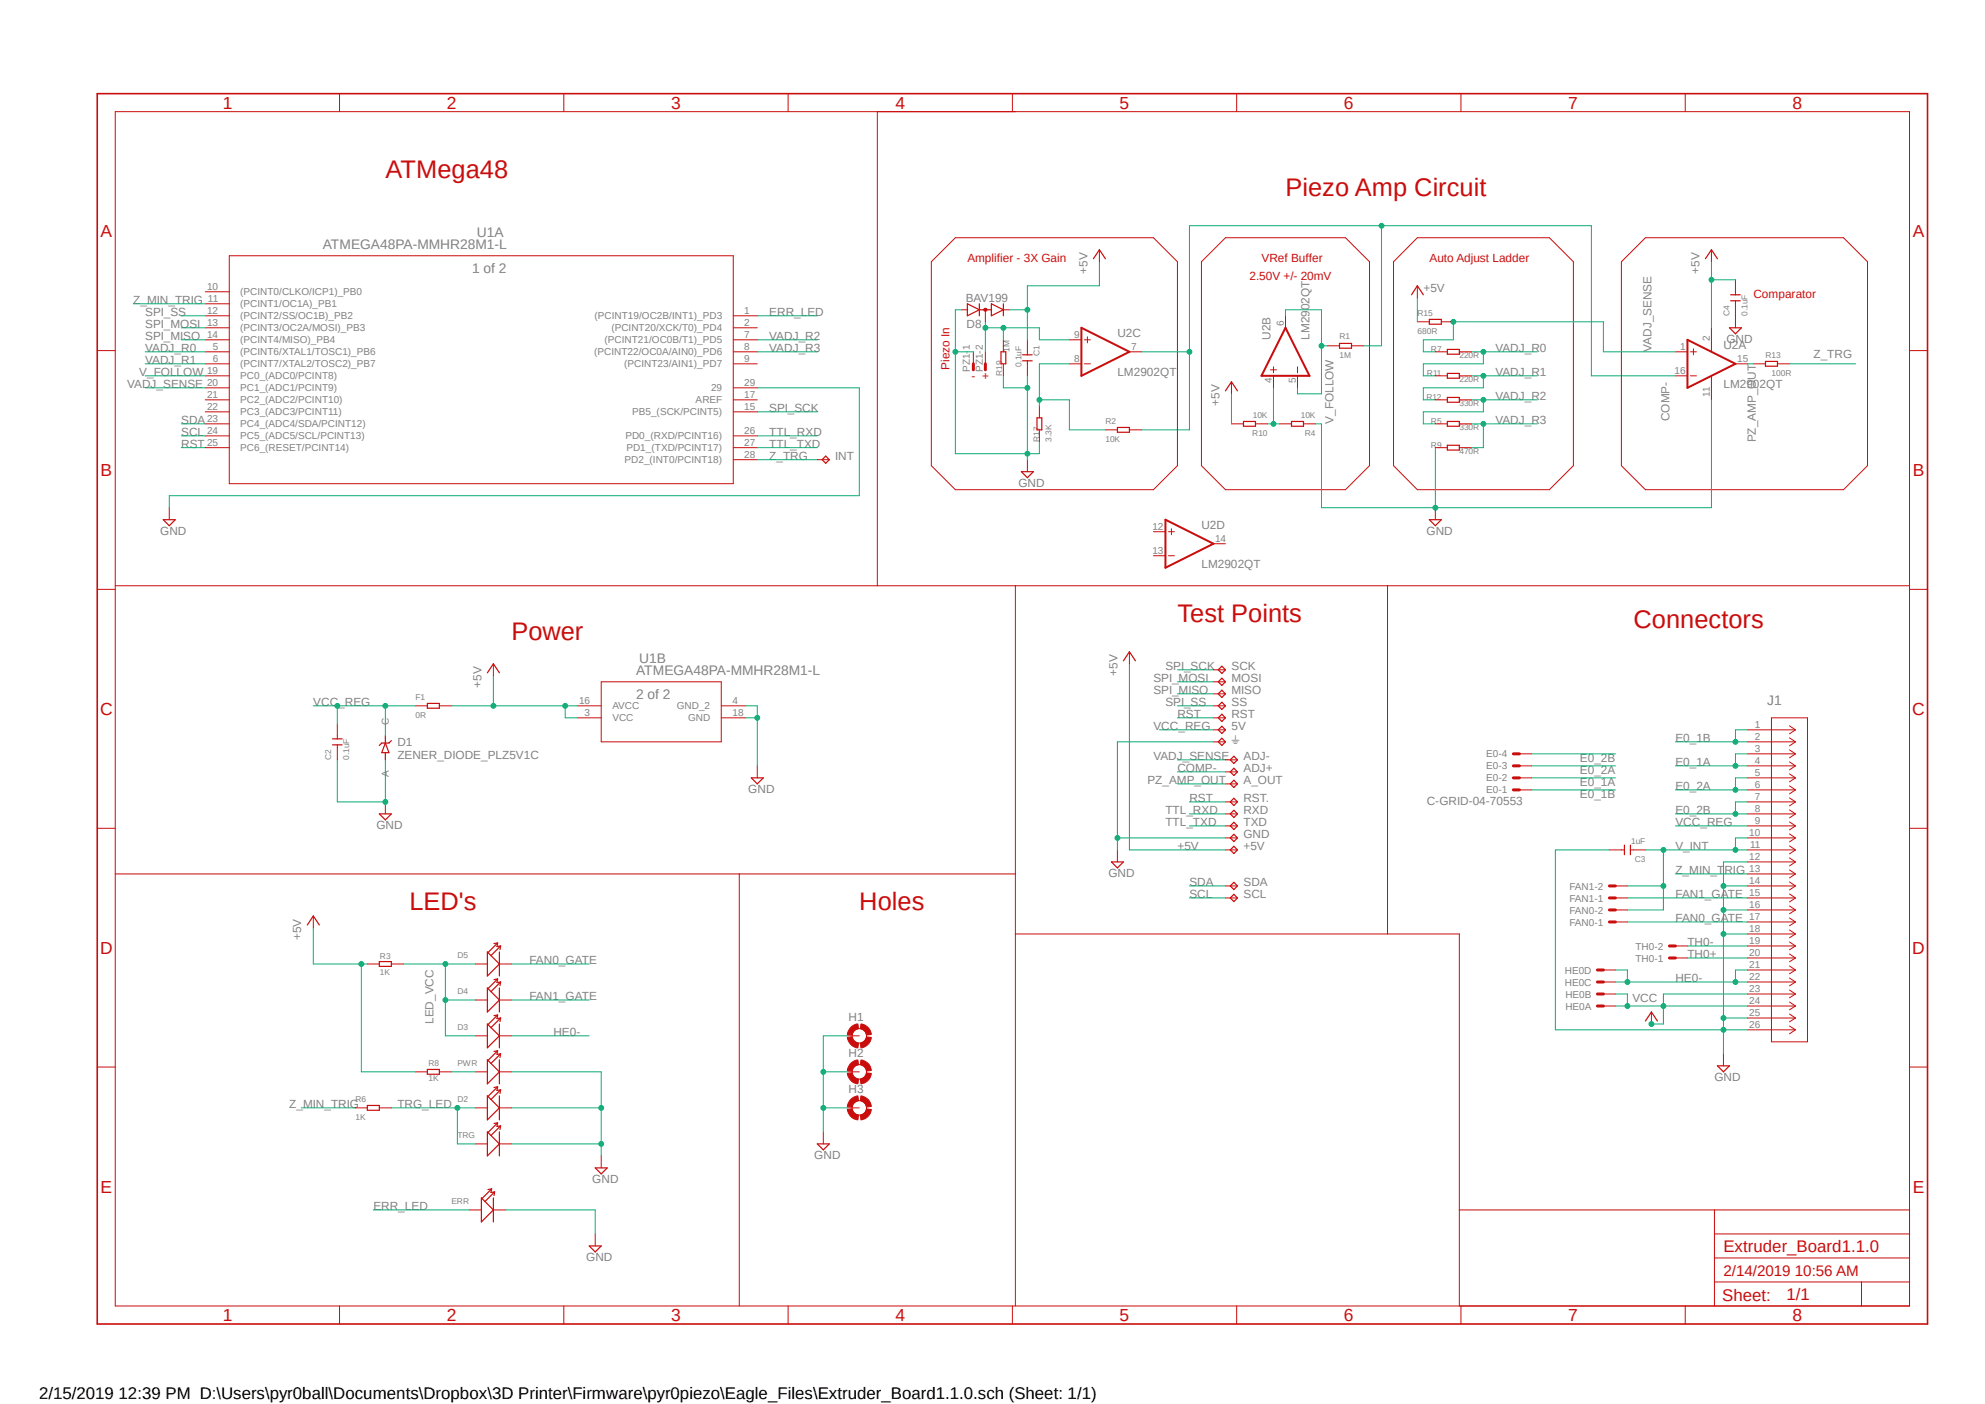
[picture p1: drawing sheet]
<svg xmlns="http://www.w3.org/2000/svg" width="420mm" height="297mm" viewBox="0 0 420 297" stroke-linecap="round" stroke-linejoin="round" font-family="sans-serif">
<defs><g id="words">
<g font-size="5.4" fill="#c90d0c">
<text x="81.5" y="37.6">ATMega48</text>
<text x="272" y="41.4">Piezo Amp Circuit</text>
<text x="249.1" y="131.5">Test Points</text>
<text x="108.2" y="135.3">Power</text>
<text x="345.6" y="132.8">Connectors</text>
<text x="86.6" y="192.5">LED's</text>
<text x="181.8" y="192.5">Holes</text>
</g>
<g font-size="3.7" fill="#c90d0c">
<text x="47.1" y="23">1</text>
<text x="94.6" y="23">2</text>
<text x="142" y="23">3</text>
<text x="189.4" y="23">4</text>
<text x="236.9" y="23">5</text>
<text x="284.4" y="23">6</text>
<text x="331.8" y="23">7</text>
<text x="379.3" y="23">8</text>
<text x="21.3" y="50.2">A</text>
<text x="404.7" y="50.2">A</text>
<text x="21.3" y="100.7">B</text>
<text x="404.7" y="100.7">B</text>
<text x="21.2" y="151.3">C</text>
<text x="404.6" y="151.3">C</text>
<text x="21.2" y="201.8">D</text>
<text x="404.6" y="201.8">D</text>
<text x="21.3" y="252.3">E</text>
<text x="404.7" y="252.3">E</text>
<text x="47.1" y="279.5">1</text>
<text x="94.6" y="279.5">2</text>
<text x="142" y="279.5">3</text>
<text x="189.4" y="279.5">4</text>
<text x="236.9" y="279.5">5</text>
<text x="284.4" y="279.5">6</text>
<text x="331.8" y="279.5">7</text>
<text x="379.3" y="279.5">8</text>
</g>
<g font-size="3.6" fill="#c90d0c">
<text x="364.7" y="264.8">Extruder_Board1.1.0</text>
<text x="364.4" y="275.1">Sheet:</text>
<text x="378" y="275">1/1</text>
</g>
<text font-size="3.6" x="8.3" y="295.9">2/15/2019 12:39 PM D:\Users\pyr0ball\Documents\Dropbox\3D Printer\Firmware\pyr0piezo\Eagle_Files\Extruder_Board1.1.0.sch (Sheet: 1/1)</text>
<text font-size="3.2" fill="#c90d0c" x="364.7" y="269.9">2/14/2019 10:56 AM</text>
<g font-size="2.9" fill="#808080">
<text x="68.3" y="52.6">ATMEGA48PA-MMHR28M1-L</text>
<text x="100.9" y="50">U1A</text>
<text x="99.9" y="57.7">1 of 2</text>
<text x="134.6" y="142.7">ATMEGA48PA-MMHR28M1-L</text>
<text x="135.2" y="140.2">U1B</text>
<text x="134.6" y="147.8">2 of 2</text>
<text x="373.9" y="149.1">J1</text>
</g>
<g font-size="2.5" fill="#c90d0c">
<text x="204.7" y="55.4">Amplifier - 3X Gain</text>
<text x="264.4" y="59.2">2.50V +/- 20mV</text>
<text x="266.9" y="55.4">VRef Buffer</text>
<text x="302.5" y="55.4">Auto Adjust Ladder</text>
<text x="371" y="63">Comparator</text>
<text x="200.9" y="78.2" transform="rotate(-90 200.9 78.2)">Piezo In</text>
<text x="205.6" y="80.4">- +</text>
</g>
<g font-size="2.5" fill="#808080">
<text x="230.1" y="57.9" transform="rotate(-90 230.1 57.9)">+5V</text>
<text x="359.6" y="57.9" transform="rotate(-90 359.6 57.9)">+5V</text>
<text x="28.2" y="64.3">Z_MIN_TRIG</text>
<text x="204.3" y="63.8">BAV199</text>
<text x="301.2" y="61.7">+5V</text>
<text x="30.7" y="71.9">SPI_MISO</text>
<text x="30.7" y="69.3">SPI_MOSI</text>
<text x="30.7" y="66.8">SPI_SS</text>
<text x="162.8" y="71.9">VADJ_R2</text>
<text x="162.8" y="66.8">ERR_LED</text>
<text x="204.5" y="69.3">D8</text>
<text x="236.4" y="71.2">U2C</text>
<text x="268.8" y="71.9" transform="rotate(-90 268.8 71.9)">U2B</text>
<text x="277.1" y="71.9" transform="rotate(-90 277.1 71.9)">LM2902QT</text>
<text x="30.7" y="74.4">VADJ_R0</text>
<text x="30.7" y="77">VADJ_R1</text>
<text x="162.8" y="74.4">VADJ_R3</text>
<text x="316.4" y="74.4">VADJ_R0</text>
<text x="349.4" y="74.4" transform="rotate(-90 349.4 74.4)">VADJ_SENSE</text>
<text x="364.7" y="73.8">U2A</text>
<text x="365.3" y="72.5">GND</text>
<text x="383.7" y="75.7">Z_TRG</text>
<text x="26.9" y="82">VADJ_SENSE</text>
<text x="29.5" y="79.5">V_FOLLOW</text>
<text x="236.4" y="79.5">LM2902QT</text>
<text x="316.4" y="79.5">VADJ_R1</text>
<text x="364.7" y="82">LM2902QT</text>
<text x="38.4" y="89.7">SDA</text>
<text x="162.8" y="87.1">SPI_SCK</text>
<text x="258" y="85.9" transform="rotate(-90 258 85.9)">+5V</text>
<text x="282.2" y="89.7" transform="rotate(-90 282.2 89.7)">V_FOLLOW</text>
<text x="316.4" y="84.6">VADJ_R2</text>
<text x="316.4" y="89.7">VADJ_R3</text>
<text x="353.2" y="89.1" transform="rotate(-90 353.2 89.1)">COMP-</text>
<text x="38.4" y="94.7">RST</text>
<text x="38.4" y="92.2">SCL</text>
<text x="162.8" y="92.2">TTL_RXD</text>
<text x="162.8" y="94.7">TTL_TXD</text>
<text x="371.5" y="93.6" transform="rotate(-90 371.5 93.6)">PZ_AMP_OUT</text>
<text x="162.8" y="97.2">Z_TRG</text>
<text x="176.7" y="97.2">INT</text>
<text x="215.5" y="103">GND</text>
<text x="33.9" y="113.1">GND</text>
<text x="254.2" y="111.8">U2D</text>
<text x="301.8" y="113.1">GND</text>
<text x="254.2" y="120.1">LM2902QT</text>
<text x="236.4" y="143" transform="rotate(-90 236.4 143)">+5V</text>
<text x="246.6" y="141.7">SPI_SCK</text>
<text x="260.6" y="141.7">SCK</text>
<text x="66.3" y="149.3">VCC_REG</text>
<text x="101.9" y="145.5" transform="rotate(-90 101.9 145.5)">+5V</text>
<text x="244.1" y="146.8">SPI_MISO</text>
<text x="244.1" y="144.2">SPI_MOSI</text>
<text x="246.6" y="149.3">SPI_SS</text>
<text x="260.6" y="144.2">MOSI</text>
<text x="260.6" y="146.8">MISO</text>
<text x="260.6" y="149.3">SS</text>
<text x="244.1" y="154.4">VCC_REG</text>
<text x="249.1" y="151.9">RST</text>
<text x="260.6" y="151.9">RST</text>
<text x="260.6" y="154.4">5V</text>
<text x="84.1" y="160.5">ZENER_DIODE_PLZ5V1C</text>
<text x="84.1" y="157.7">D1</text>
<text x="244.1" y="160.7">VADJ_SENSE</text>
<text x="260.6" y="157.4">⏚</text>
<text x="263.1" y="160.7">ADJ-</text>
<text x="334.3" y="161.2">E0_2B</text>
<text x="354.5" y="156.9">E0_1B</text>
<text x="158.3" y="167.7">GND</text>
<text x="242.8" y="165.8">PZ_AMP_OUT</text>
<text x="249.1" y="163.3">COMP-</text>
<text x="263.1" y="163.3">ADJ+</text>
<text x="263.1" y="165.8">A_OUT</text>
<text x="334.3" y="163.8">E0_2A</text>
<text x="334.3" y="166.3">E0_1A</text>
<text x="354.5" y="167.1">E0_2A</text>
<text x="354.5" y="162">E0_1A</text>
<text x="246.6" y="172.2">TTL_RXD</text>
<text x="251.7" y="169.6">RST</text>
<text x="263.1" y="172.2">RXD</text>
<text x="263.1" y="169.6">RST.</text>
<text x="301.9" y="170.3">C-GRID-04-70553</text>
<text x="334.3" y="168.9">E0_1B</text>
<text x="354.5" y="172.2">E0_2B</text>
<text x="79.6" y="175.3">GND</text>
<text x="246.6" y="174.7">TTL_TXD</text>
<text x="249.1" y="179.8">+5V</text>
<text x="263.1" y="174.7">TXD</text>
<text x="263.1" y="177.2">GND</text>
<text x="263.1" y="179.8">+5V</text>
<text x="354.5" y="179.8">V_INT</text>
<text x="354.5" y="174.7">VCC_REG</text>
<text x="234.5" y="185.5">GND</text>
<text x="354.5" y="184.9">Z_MIN_TRIG</text>
<text x="251.7" y="187.4">SDA</text>
<text x="251.7" y="190">SCL</text>
<text x="263.1" y="187.4">SDA</text>
<text x="263.1" y="190">SCL</text>
<text x="354.5" y="190">FAN1_GATE</text>
<text x="354.5" y="195">FAN0_GATE</text>
<text x="63.8" y="198.8" transform="rotate(-90 63.8 198.8)">+5V</text>
<text x="112" y="203.9">FAN0_GATE</text>
<text x="357" y="202.7">TH0+</text>
<text x="357" y="200.1">TH0-</text>
<text x="354.5" y="207.7">HE0-</text>
<text x="112" y="211.5">FAN1_GATE</text>
<text x="345.4" y="212">VCC</text>
<text x="91.7" y="216.6" transform="rotate(-90 91.7 216.6)">LED_VCC</text>
<text x="117.1" y="219.2">HE0-</text>
<text x="179.5" y="216">H1</text>
<text x="179.5" y="223.6">H2</text>
<text x="179.5" y="231.3">H3</text>
<text x="362.8" y="228.6">GND</text>
<text x="61.2" y="234.4">Z_MIN_TRIG</text>
<text x="84.1" y="234.4">TRG_LED</text>
<text x="172.3" y="245.2">GND</text>
<text x="125.3" y="250.2">GND</text>
<text x="79" y="255.9">ERR_LED</text>
<text x="124" y="266.7">GND</text>
</g>
<g font-size="2.1" fill="#808080">
<text x="43.8" y="61.3">10</text>
<text x="44" y="63.9">11</text>
<text x="50.8" y="62.5">(PCINT0/CLKO/ICP1)_PB0</text>
<text x="50.8" y="65">(PCINT1/OC1A)_PB1</text>
<text x="43.8" y="66.4">12</text>
<text x="43.8" y="69">13</text>
<text x="43.8" y="71.5">14</text>
<text x="50.8" y="67.6">(PCINT2/SS/OC1B)_PB2</text>
<text x="50.8" y="70.1">(PCINT3/OC2A/MOSI)_PB3</text>
<text x="125.8" y="67.6">(PCINT19/OC2B/INT1)_PD3</text>
<text x="129.4" y="70.1">(PCINT20/XCK/T0)_PD4</text>
<text x="157.5" y="66.4">1</text>
<text x="157.5" y="69">2</text>
<text x="157.5" y="71.5">7</text>
<text x="227.3" y="71.5">9</text>
<text x="271.6" y="69" transform="rotate(-90 271.6 69)">6</text>
<text x="45" y="74">5</text>
<text x="45" y="76.6">6</text>
<text x="50.8" y="72.6">(PCINT4/MISO)_PB4</text>
<text x="50.8" y="75.2">(PCINT6/XTAL1/TOSC1)_PB6</text>
<text x="50.8" y="77.7">(PCINT7/XTAL2/TOSC2)_PB7</text>
<text x="125.7" y="75.2">(PCINT22/OC0A/AIN0)_PD6</text>
<text x="127.9" y="72.6">(PCINT21/OC0B/T1)_PD5</text>
<text x="132.1" y="77.7">(PCINT23/AIN1)_PD7</text>
<text x="157.5" y="74">8</text>
<text x="157.5" y="76.6">9</text>
<text x="227.3" y="76.6">8</text>
<text x="239.3" y="74">7</text>
<text x="355.5" y="74">1</text>
<text x="361.8" y="72.1" transform="rotate(-90 361.8 72.1)">2</text>
<text x="367.6" y="76.6">15</text>
<text x="43.8" y="79.1">19</text>
<text x="43.8" y="81.7">20</text>
<text x="50.8" y="80.3">PC0_(ADC0/PCINT8)</text>
<text x="50.8" y="82.8">PC1_(ADC1/PCINT9)</text>
<text x="150.5" y="82.8">29</text>
<text x="157.5" y="81.7">29</text>
<text x="205.2" y="78.7" transform="rotate(-90 205.2 78.7)">PZ1-1</text>
<text x="208" y="78.7" transform="rotate(-90 208 78.7)">PZ1-2</text>
<text x="269.1" y="81" transform="rotate(-90 269.1 81)">4</text>
<text x="274.2" y="81" transform="rotate(-90 274.2 81)">5</text>
<text x="354.3" y="79.1">16</text>
<text x="43.8" y="84.2">21</text>
<text x="43.8" y="86.7">22</text>
<text x="43.8" y="89.3">23</text>
<text x="50.8" y="85.3">PC2_(ADC2/PCINT10)</text>
<text x="50.8" y="87.9">PC3_(ADC3/PCINT11)</text>
<text x="133.8" y="87.9">PB5_(SCK/PCINT5)</text>
<text x="147.2" y="85.3">AREF</text>
<text x="157.5" y="84.2">17</text>
<text x="157.5" y="86.7">15</text>
<text x="361.8" y="84" transform="rotate(-90 361.8 84)">11</text>
<text x="43.8" y="91.8">24</text>
<text x="43.8" y="94.4">25</text>
<text x="50.8" y="90.4">PC4_(ADC4/SDA/PCINT12)</text>
<text x="50.8" y="93">PC5_(ADC5/SCL/PCINT13)</text>
<text x="50.8" y="95.5">PC6_(RESET/PCINT14)</text>
<text x="132.3" y="93">PD0_(RXD/PCINT16)</text>
<text x="132.5" y="95.5">PD1_(TXD/PCINT17)</text>
<text x="157.5" y="91.8">26</text>
<text x="157.5" y="94.4">27</text>
<text x="132.2" y="98">PD2_(INT0/PCINT18)</text>
<text x="157.5" y="96.9">28</text>
<text x="243.8" y="112.1">12</text>
<text x="243.8" y="117.2">13</text>
<text x="257.1" y="114.7">14</text>
<text x="122.5" y="149">16</text>
<text x="155" y="149">4</text>
<text x="82.3" y="153.3" transform="rotate(-90 82.3 153.3)">C</text>
<text x="123.7" y="151.5">3</text>
<text x="129.6" y="150.1">AVCC</text>
<text x="129.6" y="152.6">VCC</text>
<text x="143.2" y="150.1">GND_2</text>
<text x="145.6" y="152.6">GND</text>
<text x="155" y="151.5">18</text>
<text x="371.3" y="154.1">1</text>
<text x="314.5" y="160.2">E0-4</text>
<text x="371.3" y="156.6">2</text>
<text x="371.3" y="159.1">3</text>
<text x="371.3" y="161.7">4</text>
<text x="82.3" y="164.5" transform="rotate(-90 82.3 164.5)">A</text>
<text x="314.5" y="167.9">E0-1</text>
<text x="314.5" y="165.3">E0-2</text>
<text x="314.5" y="162.8">E0-3</text>
<text x="371.3" y="164.2">5</text>
<text x="371.3" y="166.8">6</text>
<text x="371.3" y="169.3">7</text>
<text x="371.3" y="171.8">8</text>
<text x="370.1" y="176.9">10</text>
<text x="370.3" y="179.4">11</text>
<text x="371.3" y="174.3">9</text>
<text x="370.1" y="181.9">12</text>
<text x="370.1" y="184.5">13</text>
<text x="332.1" y="190.7">FAN1-1</text>
<text x="332.1" y="188.2">FAN1-2</text>
<text x="370.1" y="187">14</text>
<text x="370.1" y="189.6">15</text>
<text x="332.1" y="195.8">FAN0-1</text>
<text x="332.1" y="193.3">FAN0-2</text>
<text x="370.1" y="192.1">16</text>
<text x="370.1" y="194.6">17</text>
<text x="370.1" y="197.2">18</text>
<text x="346" y="203.4">TH0-1</text>
<text x="346" y="200.9">TH0-2</text>
<text x="370.1" y="199.7">19</text>
<text x="370.1" y="202.3">20</text>
<text x="331.1" y="208.5">HE0C</text>
<text x="331.1" y="206">HE0D</text>
<text x="370.1" y="204.8">21</text>
<text x="370.1" y="207.3">22</text>
<text x="370.1" y="209.9">23</text>
<text x="331.2" y="213.6">HE0A</text>
<text x="331.2" y="211">HE0B</text>
<text x="370.1" y="212.4">24</text>
<text x="370.1" y="215">25</text>
<text x="370.1" y="217.5">26</text>
</g>
<g font-size="1.8" fill="#808080">
<text x="283.4" y="71.6">R1</text>
<text x="299.9" y="70.6">680R</text>
<text x="299.9" y="66.8">R15</text>
<text x="365.9" y="66.8" transform="rotate(-90 365.9 66.8)">C4</text>
<text x="369.7" y="66.8" transform="rotate(-90 369.7 66.8)">0.1uF</text>
<text x="213.6" y="74.4" transform="rotate(-90 213.6 74.4)">1M</text>
<text x="216.1" y="77.7" transform="rotate(-90 216.1 77.7)">0.1uF</text>
<text x="219.9" y="75.4" transform="rotate(-90 219.9 75.4)">C1</text>
<text x="283.4" y="75.7">1M</text>
<text x="302.8" y="74.4">R7</text>
<text x="308.8" y="75.7">220R</text>
<text x="373.5" y="75.7">R13</text>
<text x="212" y="79.5" transform="rotate(-90 212 79.5)">R19</text>
<text x="301.9" y="79.5">R11</text>
<text x="308.8" y="80.8">220R</text>
<text x="374.8" y="79.5">100R</text>
<text x="233.9" y="89.7">R2</text>
<text x="265" y="88.4">10K</text>
<text x="275.2" y="88.4">10K</text>
<text x="301.8" y="84.6">R12</text>
<text x="302.8" y="89.7">R5</text>
<text x="308.8" y="85.9">330R</text>
<text x="219.9" y="93.5" transform="rotate(-90 219.9 93.5)">R17</text>
<text x="222.5" y="93.5" transform="rotate(-90 222.5 93.5)">3.3K</text>
<text x="233.9" y="93.5">10K</text>
<text x="265" y="92.2">R10</text>
<text x="276.1" y="92.2">R4</text>
<text x="302.8" y="94.7">R9</text>
<text x="308.8" y="90.9">330R</text>
<text x="308.8" y="96">470R</text>
<text x="87.9" y="148">F1</text>
<text x="87.9" y="151.8">0R</text>
<text x="70.1" y="160.7" transform="rotate(-90 70.1 160.7)">C2</text>
<text x="73.9" y="160.7" transform="rotate(-90 73.9 160.7)">0.1uF</text>
<text x="345.1" y="178.5">1uF</text>
<text x="345.9" y="182.3">C3</text>
<text x="80.4" y="202.8">R3</text>
<text x="96.8" y="202.7">D5</text>
<text x="80.4" y="206.2">1K</text>
<text x="96.8" y="210.3">D4</text>
<text x="96.8" y="217.9">D3</text>
<text x="90.7" y="225.6">R8</text>
<text x="96.8" y="225.5">PWR</text>
<text x="75.2" y="233.1">R6</text>
<text x="90.7" y="228.8">1K</text>
<text x="96.8" y="233.1">D2</text>
<text x="75.2" y="236.9">1K</text>
<text x="96.8" y="240.7">TRG</text>
<text x="95.5" y="254.7">ERR</text>
</g>
</g></defs>
<path d="M20.1 19.5l388.1 261.1M408.2 19.5l-388.1 261.1" fill="none" stroke="#fff" stroke-width=".21"/>
<g fill="none" stroke="#c90d0c" stroke-width=".21">
<path d="M214.8 23.6h-29.2v100.3M48.5 54.1h106.7v48.2h-106.7zM202.1 50.3h42l5 5.1v43.1l-5 5.1h-42l-5-5.1v-43.1zM259.3 50.3h25.4l5.1 5.1v43.1l-5.1 5.1h-25.4l-5.1-5.1v-43.1zM299.9 50.3h27.9l5.1 5.1v43.1l-5.1 5.1h-27.9l-5-5.1v-43.1zM348.1 50.3h42l5 5.1v43.1l-5 5.1h-42l-5-5.1v-43.1zM43.4 66.8h5.1M43.4 69.3h5.1M43.4 71.9h5.1M43.4 74.4h5.1M43.4 77h5.1M43.4 61.7h5.1"/>
<path d="M43.4 64.3h5.1M43.4 79.5h5.1M155.2 66.8h5M155.2 69.3h5M155.2 71.9h5M155.2 74.4h5M155.2 77h5M206 74.4v2.6M208.5 74.4v2.6M43.4 82h5.1M43.4 84.6h5.1M43.4 87.1h5.1"/>
<path d="M43.4 92.2h5.1M43.4 94.7h5.1M43.4 89.7h5.1M155.2 82h5M155.2 84.6h5M155.2 87.1h5M155.2 92.2h5M155.2 94.7h5M155.2 97.2h5M24.4 123.9h379.6M214.8 123.9v152.4M293.6 123.9v73.7"/>
<path d="M122.1 149.3h5.1M122.1 151.8h5.1M127.2 144.2h25.4v12.7h-25.4zM152.6 149.3h5.1M152.6 151.8h5.1M321.5 159.5h2.5M369.7 156.9h10.2M369.7 154.4h10.2M369.7 159.5h10.2M374.8 151.8h7.6v68.6h-7.6zM378.6 153.5l1.3 .9M378.6 156.1l1.3 .8"/>
<path d="M378.6 158.6l1.3 .9M379.9 154.4l-1.3 .8M379.9 156.9l-1.3 .9M379.9 159.5l-1.3 .8M81.5 169.6v2.6M160.2 162v2.5M321.5 162h2.5M321.5 164.5h2.5M321.5 167.1h2.5M369.7 162h10.2M369.7 164.5h10.2M369.7 167.1h10.2"/>
<path d="M369.7 169.6h10.2M369.7 172.2h10.2M369.7 174.7h10.2M369.7 177.2h10.2M369.7 179.8h10.2M378.6 161.2l1.3 .8M378.6 163.7l1.3 .8M378.6 166.2l1.3 .9M378.6 168.8l1.3 .8M378.6 171.3l1.3 .9M378.6 173.9l1.3 .8M378.6 176.4l1.3 .8"/>
<path d="M378.6 178.9l1.3 .9M379.9 162l-1.3 .9M379.9 164.5l-1.3 .9M379.9 167.1l-1.3 .8M379.9 169.6l-1.3 .9M379.9 172.2l-1.3 .8M379.9 174.7l-1.3 .9M379.9 177.2l-1.3 .9M379.9 179.8l-1.3 .8M24.4 184.9h190.4M156.4 184.9v91.4M214.8 197.6h94v58.3"/>
<path d="M341.8 187.4h2.5M341.8 189.9h2.5M341.8 192.5h2.5M341.8 195h2.5M369.7 184.9h10.2M369.7 197.6h10.2M369.7 182.3h10.2M369.7 187.4h10.2M369.7 189.9h10.2M369.7 192.5h10.2M369.7 195h10.2M378.6 181.5l1.3 .8"/>
<path d="M378.6 184l1.3 .9M378.6 186.6l1.3 .8M378.6 189.1l1.3 .8M378.6 191.6l1.3 .9M378.6 194.2l1.3 .8M378.6 196.7l1.3 .9M378.6 199.3l1.3 .8M379.9 182.3l-1.3 .9M379.9 184.9l-1.3 .8M379.9 187.4l-1.3 .9M379.9 189.9l-1.3 .9M379.9 192.5l-1.3 .8"/>
<path d="M379.9 195l-1.3 .8M379.9 197.6l-1.3 .8M100.6 219.1h2.5M100.6 211.5h2.5M100.6 203.9h2.5M105.7 219.1h2.5M105.7 211.5h2.5M105.7 203.9h2.5M339.3 205.2h2.5M339.3 207.7h2.5M339.3 210.3h2.5M339.3 212.8h2.5"/>
<path d="M349.4 214.1v2.5M354.5 200.1h2.5M354.5 202.6h2.5M369.7 200.1h10.2M369.7 202.6h10.2M369.7 205.2h10.2M369.7 207.7h10.2M369.7 210.3h10.2M369.7 212.8h10.2M369.7 215.3h10.2M369.7 217.8h10.2M378.6 201.8l1.3 .8"/>
<path d="M378.6 204.3l1.3 .9M378.6 206.9l1.3 .8M378.6 209.4l1.3 .9M378.6 212l1.3 .8M378.6 214.5l1.3 .8M378.6 217l1.3 .8M379.9 200.1l-1.3 .8M379.9 202.6l-1.3 .9M379.9 205.2l-1.3 .8M379.9 207.7l-1.3 .8M379.9 210.3l-1.3 .8M379.9 212.8l-1.3 .8"/>
<path d="M379.9 215.3l-1.3 .9M379.9 217.8l-1.3 .9M100.6 234.4h2.5M105.7 234.4h2.5M364.7 222.9v2.6"/>
<circle cx="181.8" cy="219.1" r="1.53"/>
</g>
<g fill="none" stroke="#c90d0c" stroke-width=".63">
<path d="M206 77v1.2M208.5 77v1.2M320.2 159.5h1.3M320.2 167.1h1.3M320.2 164.5h1.3M320.2 162h1.3M340.5 189.9h1.3M340.5 187.4h1.3M340.5 195h1.3M340.5 192.5h1.3M338 212.8h1.3M338 210.3h1.3"/>
<path d="M338 207.7h1.3M338 205.2h1.3M353.2 202.6h1.3M353.2 200.1h1.3"/>
</g>
<g fill="none" stroke="#c90d0c" stroke-width=".25">
<path d="M80.3 172.2h2.5l-1.3 1.2zM159 164.5h2.5l-1.3 1.3zM105.3 199.5l-2 2M105.3 199.5l-.8 .1M105.3 199.5l-.1 .7 .7-.1M103.1 201.4l2.6 2.5-2.6 2.6zM103.1 209l2.6 2.5-2.6 2.6zM103.1 216.6l2.6 2.5-2.6 2.6zM105.3 214.7l-2 2M105.3 214.7l-.8 .1M105.3 214.7l-.1 .8 .7-.2M105.3 207.1l-2 2"/>
<path d="M105.3 207.1l-.8 .1M105.3 207.1l-.1 .8 .7-.2M105.7 201.4v5.1M105.7 209v5.1M105.7 216.6v5.1M105.9 215.3l-2 2.1M105.9 215.3l-.1 .8M105.9 207.7l-2 2.1M105.9 207.7l-.1 .8M105.9 200.1l-2 2M105.9 200.1l-.1 .8M348.1 216l1.3-1.9 1.3 1.9"/>
<path d="M103.1 231.8l2.6 2.6-2.6 2.5zM105.3 229.9l-2 2M105.3 229.9l-.8 .1M105.3 229.9l-.1 .8 .7-.2M105.7 231.8v5.1M105.9 230.5l-2 2.1M105.9 230.5l-.1 .8M363.4 225.5h2.5l-1.2 1.2z"/>
</g>
<path d="M182.2 216.6a2.45 2.45 0 0 1 2.2 2.2l-1.1 .1a1.57 1.57 0 0 0-1.3-1.3z" fill-rule="evenodd" fill="#c90d0c"/>
<path d="M182.2 216.6a2.45 2.45 0 0 1 2.2 2.2l-1.1 .1a1.57 1.57 0 0 0-1.3-1.3z" fill="none" stroke="#c90d0c" stroke-width=".21"/>
<path d="M180.2 217.1l.5-.3 .8-.2 .2 1a1.56 1.56 0 0 0-1.4 1.3l-1-.1a2.86 2.86 0 0 1 .9-1.7z" fill-rule="evenodd" fill="#c90d0c"/>
<path d="M180.2 217.1l.5-.3 .8-.2 .2 1a1.56 1.56 0 0 0-1.4 1.3l-1-.1a2.86 2.86 0 0 1 .9-1.7z" fill="none" stroke="#c90d0c" stroke-width=".21"/>
<path d="M179.3 219.5l1-.2a1.56 1.56 0 0 0 1.4 1.4l-.2 1a2.44 2.44 0 0 1-2.2-2.2z" fill-rule="evenodd" fill="#c90d0c"/>
<path d="M179.3 219.5l1-.2a1.56 1.56 0 0 0 1.4 1.4l-.2 1a2.44 2.44 0 0 1-2.2-2.2z" fill="none" stroke="#c90d0c" stroke-width=".21"/>
<path d="M183.3 219.3l1.1 .2a2.45 2.45 0 0 1-2.2 2.2l-.2-1a1.57 1.57 0 0 0 1.3-1.4z" fill-rule="evenodd" fill="#c90d0c"/>
<g fill="none" stroke="#c90d0c" stroke-width=".21">
<path d="M179.3 219.1h2.5M183.3 219.3l1.1 .2a2.45 2.45 0 0 1-2.2 2.2l-.2-1a1.57 1.57 0 0 0 1.3-1.4z"/>
<circle cx="181.8" cy="226.7" r="1.53"/>
</g>
<path d="M182.2 224.2a2.45 2.45 0 0 1 2.2 2.2l-1.1 .2a1.57 1.57 0 0 0-1.3-1.4z" fill-rule="evenodd" fill="#c90d0c"/>
<path d="M182.2 224.2a2.45 2.45 0 0 1 2.2 2.2l-1.1 .2a1.57 1.57 0 0 0-1.3-1.4z" fill="none" stroke="#c90d0c" stroke-width=".21"/>
<path d="M180.2 224.7l.5-.2 .8-.3 .2 1a1.56 1.56 0 0 0-1.4 1.4l-1-.2a2.86 2.86 0 0 1 .9-1.7z" fill-rule="evenodd" fill="#c90d0c"/>
<path d="M180.2 224.7l.5-.2 .8-.3 .2 1a1.56 1.56 0 0 0-1.4 1.4l-1-.2a2.86 2.86 0 0 1 .9-1.7z" fill="none" stroke="#c90d0c" stroke-width=".21"/>
<path d="M179.3 227.1l1-.2a1.56 1.56 0 0 0 1.4 1.4l-.2 1a2.44 2.44 0 0 1-2.2-2.2z" fill-rule="evenodd" fill="#c90d0c"/>
<path d="M179.3 227.1l1-.2a1.56 1.56 0 0 0 1.4 1.4l-.2 1a2.44 2.44 0 0 1-2.2-2.2z" fill="none" stroke="#c90d0c" stroke-width=".21"/>
<path d="M183.3 226.9l1.1 .2a2.45 2.45 0 0 1-2.2 2.2l-.2-1a1.57 1.57 0 0 0 1.3-1.4z" fill-rule="evenodd" fill="#c90d0c"/>
<g fill="none" stroke="#c90d0c" stroke-width=".21">
<path d="M179.3 226.7h2.5M183.3 226.9l1.1 .2a2.45 2.45 0 0 1-2.2 2.2l-.2-1a1.57 1.57 0 0 0 1.3-1.4z"/>
<circle cx="181.8" cy="234.4" r="1.53"/>
</g>
<path d="M182.2 231.8a2.57 2.57 0 0 1 2.2 2.3l-1.1 .1a1.57 1.57 0 0 0-1.3-1.4z" fill-rule="evenodd" fill="#c90d0c"/>
<path d="M182.2 231.8a2.57 2.57 0 0 1 2.2 2.3l-1.1 .1a1.57 1.57 0 0 0-1.3-1.4z" fill="none" stroke="#c90d0c" stroke-width=".21"/>
<path d="M180.2 232.4l1.3-.6 .2 1a1.56 1.56 0 0 0-1.4 1.4l-1-.1a2.86 2.86 0 0 1 .9-1.7z" fill-rule="evenodd" fill="#c90d0c"/>
<path d="M180.2 232.4l1.3-.6 .2 1a1.56 1.56 0 0 0-1.4 1.4l-1-.1a2.86 2.86 0 0 1 .9-1.7z" fill="none" stroke="#c90d0c" stroke-width=".21"/>
<path d="M179.3 234.7l1-.1a1.46 1.46 0 0 0 1.4 1.3l-.2 1a2.44 2.44 0 0 1-2.2-2.2z" fill-rule="evenodd" fill="#c90d0c"/>
<path d="M179.3 234.7l1-.1a1.46 1.46 0 0 0 1.4 1.3l-.2 1a2.44 2.44 0 0 1-2.2-2.2z" fill="none" stroke="#c90d0c" stroke-width=".21"/>
<path d="M183.3 234.6l1.1 .1a2.45 2.45 0 0 1-2.2 2.2l-.2-1a1.47 1.47 0 0 0 1.3-1.3z" fill-rule="evenodd" fill="#c90d0c"/>
<g fill="none" stroke="#c90d0c" stroke-width=".21">
<path d="M71.8 19.8v3.8M119.3 19.8v3.8M166.8 19.8v3.8M214.2 19.8v3.8M261.7 19.8v3.8M309.1 19.8v3.8M356.6 19.8v3.8M24.4 23.6h379.6v252.7h-379.6zM20.6 74.2h3.8M203.4 65.5h1.3M212.3 65.5h1.3M280.9 73.2h2.5"/>
<path d="M286 73.2h2.5M404 74.2h3.8M172.9 97.2h2.6M260.6 89.7h2.5M265.6 89.7h2.6M303.7 94.7h2.5M308.8 94.7h2.5M35.8 107.4v2.5M20.6 124.7h3.8M404 124.7h3.8M71.4 153.1v3.2M71.4 157.6v3.1"/>
<path d="M256.8 141.7h2.5M256.8 144.2h2.5M256.8 146.8h2.5M256.8 149.3h2.5M256.8 151.8h2.5M256.8 154.4h2.5M20.6 175.2h3.8M236.4 179.8v2.5M259.3 172.2h2.5M259.3 174.7h2.5M259.3 177.2h2.5M259.3 179.8h2.5"/>
<path d="M259.3 169.6h2.5M340.5 179.8h3.2M345 179.8h3.1M404 175.2h3.8M259.3 187.4h2.5M259.3 189.9h2.5M77.7 203.9h2.6M82.8 203.9h2.5M20.6 225.7h3.8M75.2 234.4h2.5M80.3 234.4h2.5M87.9 226.7h2.5"/>
<path d="M93 226.7h2.5M100.6 226.7h2.5M105.7 226.7h2.5M174.2 239.4v2.6M179.3 234.4h2.5M182 235.9a1.47 1.47 0 0 0 1.3-1.3l1.1 .1a2.45 2.45 0 0 1-2.2 2.2zM404 225.7h3.8M100.6 242h2.5M105.7 242h2.5M127.2 244.5v2.6M362.8 255.9v20.4M404 255.9h-95.2v20.4"/>
<path d="M71.8 276.3v3.8M119.3 276.3v3.8M166.8 276.3v3.8M214.2 276.3v3.8M261.7 276.3v3.8M309.1 276.3v3.8M356.6 276.3v3.8M362.8 271.2h41.2M362.8 266.1h41.2M362.8 261h41.2M393.9 271.2v5.1"/>
</g>
<g fill="none" stroke="#c90d0c" stroke-width=".25">
<path d="M204.7 64.3l2.5 1.2-2.5 1.3zM207.2 64.3v2.5M207.2 65.5h2.6M209.8 64.3l2.5 1.2-2.5 1.3zM212.3 64.3v2.5M283.4 72.6h2.6v1.1h-2.6zM174.7 96.5l.8 .7-.8 .8-.8-.8zM263.1 89.2h2.5v1h-2.5zM306.2 94.2h2.6v1h-2.6zM34.5 109.9h2.6l-1.3 1.3zM70.4 157.6h2M70.4 156.3h2"/>
<path d="M258.5 140.9l.8 .8-.8 .8-.7-.8zM258.5 143.5l.8 .7-.8 .8-.7-.8zM258.5 146l.8 .8-.8 .7-.7-.7zM258.5 148.5l.8 .8-.8 .8-.7-.8zM258.5 151.1l.8 .7-.8 .8-.7-.8zM258.5 153.6l.8 .8-.8 .8-.7-.8zM261.1 171.4l.7 .8-.7 .7-.8-.7zM261.1 173.9l.7 .8-.7 .8-.8-.8zM261.1 176.5l.7 .7-.7 .8-.8-.8zM261.1 179l.7 .8-.7 .8-.8-.8zM261.1 168.9l.7 .7-.7 .8-.8-.8zM343.7 178.8v2"/>
<path d="M345 178.8v2M235.2 182.3h2.5l-1.3 1.3zM261.1 186.6l.7 .8-.7 .8-.8-.8zM261.1 189.2l.7 .7-.7 .8-.8-.8zM80.3 203.4h2.5v1h-2.5zM77.7 233.8h2.6v1.1h-2.6zM90.4 226.2h2.6v1h-2.6zM103.1 224.2l2.6 2.5-2.6 2.6zM103.1 239.4l2.6 2.6-2.6 2.5zM105.3 237.5l-2 2.1M105.3 237.5l-.8 .2M105.3 237.5l-.1 .8 .7-.1"/>
<path d="M105.3 222.3l-2 2M105.3 222.3l-.8 .1M105.3 222.3l-.1 .8 .7-.2M105.7 224.2v5.1M105.7 239.4v5.1M105.9 238.2l-2 2M105.9 238.2l-.1 .7M105.9 222.9l-2 2.1M105.9 222.9l-.1 .8M125.9 247.1h2.6l-1.3 1.2zM172.9 242h2.6l-1.3 1.2z"/>
</g>
<path d="M20.6 19.8h387.2v260.3h-387.2z" fill="none" stroke="#c90d0c" stroke-width=".34"/>
<path d="M208.2 65.3h.5v.4l-.2 .2-.3-.2z" fill-rule="evenodd" fill="#c90d0c"/>
<g fill="none" stroke="#c90d0c" stroke-width=".21">
<path d="M232.6 52.8v2.6M362.1 52.8v2.6M367.2 59.2v3.2M208.2 65.3h.5v.4l-.2 .2-.3-.2zM208.5 65.5v2.6M212.3 71.9v2.5M212.3 77v2.5M217.4 71.9v3.2M217.4 76.3v3.2M226.3 77h2.5M226.3 71.9h2.5M229.4 77h1.3"/>
<path d="M229.4 71.9h1.3M230.1 71.2v1.3M239 74.4h2.5M268.8 78.2h1.3M269.5 77.6v1.3M269.5 79.5v2.5M272 66.8v2.5M274.5 77.6v1.3M274.5 79.5v2.5M299.9 68.1h2.5M299.9 60.5v2.5M303.7 74.4h2.5"/>
<path d="M303.7 79.5h2.5M305 68.1h2.5M308.8 74.4h2.5M308.8 79.5h2.5M354.5 74.4h2.5M354.5 79.5h2.5M357.7 74.4h1.2M357.7 79.5h1.2M358.3 73.8v1.3M362.1 69.3v5.1M362.1 79.5v5.1M367.2 77h2.5"/>
<path d="M367.2 63.6v5.7M371 77h2.5M376.1 77h2.5M217.4 97.2v2.6M219.9 85.9v2.5M219.9 90.9v2.5M233.9 90.9h2.5M239 90.9h2.5M260.6 80.8v2.5M270.7 89.7h2.6M275.8 89.7h2.5M303.7 89.7h2.5"/>
<path d="M303.7 84.6h2.5M308.8 89.7h2.5M308.8 84.6h2.5M244.1 112.5h2.5M244.1 117.6h2.5M247.2 112.5h1.3M247.2 117.6h1.3M247.9 111.8v1.3M256.8 115h2.5M303.7 107.4v2.5M239 137.9v2.5M87.9 149.3h2.5"/>
<path d="M93 149.3h2.5M104.4 140.4v2.6M256.8 156.9h2.5M259.3 160.7h2.5M259.3 163.3h2.5M259.3 165.8h2.5M66.3 193.8v2.5M99.3 255.9h2.6M104.4 255.9h2.5M125.9 261v2.6"/>
</g>
<g fill="none" stroke="#c90d0c" stroke-width=".25">
<path d="M231.4 54.7l1.2-1.9 1.3 1.9M360.8 54.7l1.3-1.9 1.3 1.9M211.8 74.4h1v2.6h-1zM216.4 75.1h2M216.4 76.3h2M298.7 62.4l1.2-1.9 1.3 1.9M302.4 67.6h2.6v1h-2.6zM306.2 73.9h2.6v1h-2.6zM306.2 79h2.6v1h-2.6zM365.9 69.3h2.6l-1.3 1.3zM366.2 63.6h2M366.2 62.4h2"/>
<path d="M373.5 76.5h2.6v1h-2.6zM216.1 99.8h2.6l-1.3 1.2zM219.4 88.4h1v2.5h-1zM236.4 90.4h2.6v1h-2.6zM259.3 82.7l1.3-1.9 1.2 1.9M273.3 89.2h2.5v1h-2.5zM306.2 89.2h2.6v1h-2.6zM306.2 84.1h2.6v1h-2.6zM302.4 109.9h2.6l-1.3 1.3zM237.7 139.8l1.3-1.9 1.2 1.9M81.5 157.2l.8 2h-1.5zM81.5 155.7v1.4"/>
<path d="M81.5 159.3v1.4M82.8 156.7l-.5 .5h-1.5l-.5 .5M90.4 148.8h2.6v1h-2.6zM103.1 142.3l1.3-1.9 1.3 1.9M258.5 156.2l.8 .7-.8 .8-.7-.8zM261.1 160l.7 .7-.7 .8-.8-.8zM261.1 162.5l.7 .8-.7 .7-.8-.7zM261.1 165.1l.7 .7-.7 .8-.8-.8zM65 195.7l1.3-1.9 1.3 1.9M101.9 253.4l2.5 2.5-2.5 2.6zM104 251.5l-2 2M104 251.5l-.7 .1"/>
<path d="M104 251.5l-.1 .8 .7-.2M104.4 253.4v5.1M104.6 252.1l-2 2.1M104.6 252.1l-.1 .8M124.7 263.6h2.5l-1.3 1.2z"/>
</g>
<path d="M228.8 69.3l10.2 5.1-10.2 5.1zM272 69.3l5.1 10.2h-10.2zM357 71.9l10.2 5.1-10.2 5zM246.6 109.9l10.2 5.1-10.2 5.1z" fill="none" stroke="#c90d0c" stroke-width=".42"/>
<path d="M157.7 151.8h2.5M157.7 149.3h2.5v12.7" fill="none" stroke="#0dab76" stroke-width=".21"/>
<circle cx="160.2" cy="151.8" r=".51" fill="#0dab76"/>
<g fill="none" stroke="#0dab76" stroke-width=".21">
<path d="M81.5 160.7v8.9"/>
<circle cx="160.2" cy="151.8" r=".51"/>
</g>
<circle cx="81.5" cy="169.6" r=".51" fill="#0dab76"/>
<g fill="none" stroke="#0dab76" stroke-width=".21">
<path d="M71.4 160.7v8.9h10.1M364.7 217.8h5M369.7 215.3h-5v7.6"/>
<circle cx="81.5" cy="169.6" r=".51"/>
</g>
<circle cx="364.7" cy="217.8" r=".51" fill="#0dab76"/>
<g fill="none" stroke="#0dab76" stroke-width=".21">
<path d="M369.7 197.6h-5v17.7"/>
<circle cx="364.7" cy="217.8" r=".51"/>
</g>
<circle cx="364.7" cy="215.3" r=".51" fill="#0dab76"/>
<g fill="none" stroke="#0dab76" stroke-width=".21">
<path d="M369.7 192.5h-5v5.1"/>
<circle cx="364.7" cy="215.3" r=".51"/>
</g>
<circle cx="364.7" cy="197.6" r=".51" fill="#0dab76"/>
<g fill="none" stroke="#0dab76" stroke-width=".21">
<path d="M369.7 187.4h-5v5.1"/>
<circle cx="364.7" cy="197.6" r=".51"/>
</g>
<circle cx="364.7" cy="192.5" r=".51" fill="#0dab76"/>
<g fill="none" stroke="#0dab76" stroke-width=".21">
<path d="M369.7 182.3h-5v5.1"/>
<circle cx="364.7" cy="192.5" r=".51"/>
</g>
<circle cx="364.7" cy="187.4" r=".51" fill="#0dab76"/>
<g fill="none" stroke="#0dab76" stroke-width=".21">
<path d="M340.5 179.8h-11.4v38h35.6M179.3 219.1h-5.1v7.6h5.1M174.2 234.4h5.1"/>
<circle cx="364.7" cy="187.4" r=".51"/>
</g>
<circle cx="174.2" cy="226.7" r=".51" fill="#0dab76"/>
<g fill="none" stroke="#0dab76" stroke-width=".21">
<path d="M174.2 226.7v7.7"/>
<circle cx="174.2" cy="226.7" r=".51"/>
</g>
<circle cx="174.2" cy="234.4" r=".51" fill="#0dab76"/>
<g fill="none" stroke="#0dab76" stroke-width=".21">
<path d="M108.2 234.4h19v10.1M174.2 234.4v5M108.2 242h19"/>
<circle cx="174.2" cy="234.4" r=".51"/>
</g>
<circle cx="127.2" cy="242" r=".51" fill="#0dab76"/>
<g fill="none" stroke="#0dab76" stroke-width=".21">
<path d="M108.2 226.7h19v7.7"/>
<circle cx="127.2" cy="242" r=".51"/>
</g>
<circle cx="127.2" cy="234.4" r=".51" fill="#0dab76"/>
<g fill="none" stroke="#0dab76" stroke-width=".21">
<path d="M256.8 156.9h-20.4v22.9M236.4 177.2h22.9"/>
<circle cx="127.2" cy="234.4" r=".51"/>
</g>
<circle cx="236.4" cy="177.2" r=".51" fill="#0dab76"/>
<g fill="none" stroke="#0dab76" stroke-width=".21">
<path d="M160.2 82h21.6v22.9h-146v2.5M362.1 84.6v22.8h-58.4v-12.7"/>
<circle cx="236.4" cy="177.2" r=".51"/>
</g>
<circle cx="303.7" cy="107.4" r=".51" fill="#0dab76"/>
<g fill="none" stroke="#0dab76" stroke-width=".21">
<path d="M217.4 79.5v2.5M217.4 96v1.2M278.3 89.7h1.3v17.7h24.1M106.9 255.9h19v5.1"/>
<circle cx="303.7" cy="107.4" r=".51"/>
</g>
<circle cx="217.4" cy="96" r=".51" fill="#0dab76"/>
<g fill="none" stroke="#0dab76" stroke-width=".21">
<path d="M203.4 65.5h-1.3v8.9h3.9M217.4 82v14h2.5"/>
<circle cx="217.4" cy="96" r=".51"/>
</g>
<circle cx="202.1" cy="74.4" r=".51" fill="#0dab76"/>
<g fill="none" stroke="#0dab76" stroke-width=".21">
<path d="M202.1 74.4v21.6h15.3M212.3 79.5v2.5h5.1"/>
<circle cx="202.1" cy="74.4" r=".51"/>
</g>
<circle cx="217.4" cy="82" r=".51" fill="#0dab76"/>
<g fill="none" stroke="#0dab76" stroke-width=".21">
<path d="M219.9 93.4v2.6M352 212.8h17.7M369.7 210.3h-17.7v6.3h-2.6"/>
<circle cx="217.4" cy="82" r=".51"/>
</g>
<circle cx="349.4" cy="216.6" r=".51" fill="#0dab76"/>
<g fill="none" stroke="#0dab76" stroke-width=".21">
<path d="M344.3 212.8h7.7"/>
<circle cx="349.4" cy="216.6" r=".51"/>
</g>
<circle cx="352" cy="212.8" r=".51" fill="#0dab76"/>
<g fill="none" stroke="#0dab76" stroke-width=".21">
<path d="M341.8 210.3h2.5v2.5h-2.5"/>
<circle cx="352" cy="212.8" r=".51"/>
</g>
<circle cx="344.3" cy="212.8" r=".51" fill="#0dab76"/>
<g fill="none" stroke="#0dab76" stroke-width=".21">
<path d="M357 202.6h12.7M357 200.1h12.7M369.7 205.2h-2.5v2.5h2.5"/>
<circle cx="344.3" cy="212.8" r=".51"/>
</g>
<circle cx="367.2" cy="207.7" r=".51" fill="#0dab76"/>
<g fill="none" stroke="#0dab76" stroke-width=".21">
<path d="M341.8 207.7h25.4M341.8 205.2h2.5v2.5"/>
<circle cx="367.2" cy="207.7" r=".51"/>
</g>
<circle cx="344.3" cy="207.7" r=".51" fill="#0dab76"/>
<g fill="none" stroke="#0dab76" stroke-width=".21">
<path d="M28.2 64.3h15.2M352 179.8h17.7M369.7 177.2h-2.5v2.6M344.3 195h25.4M344.3 189.9h25.4M354.5 184.9h15.2M108.2 219.1h16.5M108.2 203.9h16.5M108.2 211.5h16.5M63.8 234.4h11.4"/>
<circle cx="344.3" cy="207.7" r=".51"/>
</g>
<circle cx="367.2" cy="179.8" r=".51" fill="#0dab76"/>
<g fill="none" stroke="#0dab76" stroke-width=".21">
<path d="M352 179.8v12.7h-7.7M344.3 187.4h7.7"/>
<circle cx="367.2" cy="179.8" r=".51"/>
</g>
<circle cx="352" cy="187.4" r=".51" fill="#0dab76"/>
<g fill="none" stroke="#0dab76" stroke-width=".21">
<path d="M348.1 179.8h3.9"/>
<circle cx="352" cy="187.4" r=".51"/>
</g>
<circle cx="352" cy="179.8" r=".51" fill="#0dab76"/>
<g fill="none" stroke="#0dab76" stroke-width=".21">
<path d="M66.3 149.3h15.2M71.4 149.3v3.8M354.5 174.7h15.2"/>
<circle cx="352" cy="179.8" r=".51"/>
</g>
<circle cx="71.4" cy="149.3" r=".51" fill="#0dab76"/>
<g fill="none" stroke="#0dab76" stroke-width=".21">
<path d="M87.9 149.3h-6.4v6.4"/>
<circle cx="71.4" cy="149.3" r=".51"/>
</g>
<circle cx="81.5" cy="149.3" r=".51" fill="#0dab76"/>
<g fill="none" stroke="#0dab76" stroke-width=".21">
<path d="M245.3 154.4h11.5M354.5 172.2h15.2M369.7 169.6h-2.5v2.6"/>
<circle cx="81.5" cy="149.3" r=".51"/>
</g>
<circle cx="367.2" cy="172.2" r=".51" fill="#0dab76"/>
<g fill="none" stroke="#0dab76" stroke-width=".21">
<path d="M324 159.5h17.8M354.5 167.1h15.2M369.7 164.5h-2.5v2.6"/>
<circle cx="367.2" cy="172.2" r=".51"/>
</g>
<circle cx="367.2" cy="167.1" r=".51" fill="#0dab76"/>
<g fill="none" stroke="#0dab76" stroke-width=".21">
<path d="M369.7 159.5h-2.5v2.5M324 162h17.8M354.5 162h15.2"/>
<circle cx="367.2" cy="167.1" r=".51"/>
</g>
<circle cx="367.2" cy="162" r=".51" fill="#0dab76"/>
<g fill="none" stroke="#0dab76" stroke-width=".21">
<path d="M354.5 156.9h15.2M369.7 154.4h-2.5v2.5M324 164.5h17.8"/>
<circle cx="367.2" cy="162" r=".51"/>
</g>
<circle cx="367.2" cy="156.9" r=".51" fill="#0dab76"/>
<g fill="none" stroke="#0dab76" stroke-width=".21">
<path d="M324 167.1h17.8M94.2 211.5h6.4M100.6 203.9h-6.4v15.2h6.4"/>
<circle cx="367.2" cy="156.9" r=".51"/>
</g>
<circle cx="94.2" cy="211.5" r=".51" fill="#0dab76"/>
<g fill="none" stroke="#0dab76" stroke-width=".21">
<path d="M85.3 203.9h8.9"/>
<circle cx="94.2" cy="211.5" r=".51"/>
</g>
<circle cx="94.2" cy="203.9" r=".51" fill="#0dab76"/>
<g fill="none" stroke="#0dab76" stroke-width=".21">
<path d="M38.4 71.9h5M38.4 69.3h5M38.4 66.8h5M38.4 92.2h5M38.4 94.7h5M38.4 89.7h5M160.2 92.2h12.7M160.2 94.7h12.7M160.2 87.1h12.7M249.1 151.8h7.7M249.1 141.7h7.7M249.1 146.8h7.7"/>
<path d="M249.1 144.2h7.7M249.1 149.3h7.7M251.7 172.2h7.6M251.7 174.7h7.6M251.7 169.6h7.6M251.7 187.4h7.6M251.7 189.9h7.6M82.8 234.4h17.8M96.8 234.4v7.6h3.8"/>
<circle cx="94.2" cy="203.9" r=".51"/>
</g>
<circle cx="96.8" cy="234.4" r=".51" fill="#0dab76"/>
<g fill="none" stroke="#0dab76" stroke-width=".21">
<path d="M208.5 68.1v6.3M212.3 69.3h7.6M378.6 77h14M160.2 97.2h12.7M95.5 226.7h5.1"/>
<circle cx="96.8" cy="234.4" r=".51"/>
</g>
<circle cx="208.5" cy="69.3" r=".51" fill="#0dab76"/>
<g fill="none" stroke="#0dab76" stroke-width=".21">
<path d="M208.5 69.3h3.8v2.6"/>
<circle cx="208.5" cy="69.3" r=".51"/>
</g>
<circle cx="212.3" cy="69.3" r=".51" fill="#0dab76"/>
<g fill="none" stroke="#0dab76" stroke-width=".21">
<path d="M362.1 55.4v13.9M362.1 59.2h5.1M219.9 69.3v2.6h6.4"/>
<circle cx="212.3" cy="69.3" r=".51"/>
</g>
<circle cx="362.1" cy="59.2" r=".51" fill="#0dab76"/>
<g fill="none" stroke="#0dab76" stroke-width=".21">
<path d="M260.6 83.3v6.4M66.3 203.9h11.4M76.5 203.9v22.8h11.4"/>
<circle cx="362.1" cy="59.2" r=".51"/>
</g>
<circle cx="76.4" cy="203.9" r=".51" fill="#0dab76"/>
<g fill="none" stroke="#0dab76" stroke-width=".21">
<path d="M95.5 149.3h26.6M119.6 149.3v2.5h2.5M239 140.4v39.4h20.3M66.3 196.3v7.6"/>
<circle cx="76.4" cy="203.9" r=".51"/>
</g>
<circle cx="119.6" cy="149.3" r=".51" fill="#0dab76"/>
<g fill="none" stroke="#0dab76" stroke-width=".21">
<path d="M104.4 143v6.3"/>
<circle cx="119.6" cy="149.3" r=".51"/>
</g>
<circle cx="104.4" cy="149.3" r=".51" fill="#0dab76"/>
<g fill="none" stroke="#0dab76" stroke-width=".21">
<path d="M232.6 55.4v5.1h-15.2v11.4M213.6 65.5h3.8M299.9 63v5.1"/>
<circle cx="104.4" cy="149.3" r=".51"/>
</g>
<circle cx="217.4" cy="65.5" r=".51" fill="#0dab76"/>
<g fill="none" stroke="#0dab76" stroke-width=".21">
<path d="M268.2 89.7h2.5M269.5 82v7.7"/>
<circle cx="217.4" cy="65.5" r=".51"/>
</g>
<circle cx="269.4" cy="89.7" r=".51" fill="#0dab76"/>
<g fill="none" stroke="#0dab76" stroke-width=".21">
<path d="M311.3 74.4h14M313.9 74.4v2.6"/>
<circle cx="269.4" cy="89.7" r=".51"/>
</g>
<circle cx="313.9" cy="74.4" r=".51" fill="#0dab76"/>
<g fill="none" stroke="#0dab76" stroke-width=".21">
<path d="M30.7 74.4h12.7M311.3 79.5h14M313.9 77h-12.7v2.5h2.5M313.9 79.5v2.5"/>
<circle cx="313.9" cy="74.4" r=".51"/>
</g>
<circle cx="313.9" cy="79.5" r=".51" fill="#0dab76"/>
<g fill="none" stroke="#0dab76" stroke-width=".21">
<path d="M30.7 77h12.7M160.2 71.9h12.7M311.3 84.6h14M313.9 82h-12.7v2.6h2.5M313.9 84.6v2.5"/>
<circle cx="313.9" cy="79.5" r=".51"/>
</g>
<circle cx="313.9" cy="84.6" r=".51" fill="#0dab76"/>
<g fill="none" stroke="#0dab76" stroke-width=".21">
<path d="M160.2 74.4h12.7M311.3 89.7h14M313.9 87.1h-12.7v2.6h2.5M313.9 89.7v5h-2.6"/>
<circle cx="313.9" cy="84.6" r=".51"/>
</g>
<circle cx="313.9" cy="89.7" r=".51" fill="#0dab76"/>
<g fill="none" stroke="#0dab76" stroke-width=".21">
<path d="M272 66.8v-1.3h7.6v17.8h-5.1v-1.3M369.7 77h1.3M249.1 165.8h10.2"/>
<circle cx="313.9" cy="89.7" r=".51"/>
</g>
<circle cx="279.6" cy="73.2" r=".51" fill="#0dab76"/>
<g fill="none" stroke="#0dab76" stroke-width=".21">
<path d="M30.7 79.5h12.7M279.6 73.2h1.3M303.7 74.4h-2.5v-2.5h6.3v-3.8h31.8v6.3h15.2M30.7 82h12.7M249.1 160.7h10.2"/>
<circle cx="279.6" cy="73.2" r=".51"/>
</g>
<circle cx="307.5" cy="68.1" r=".51" fill="#0dab76"/>
<g fill="none" stroke="#0dab76" stroke-width=".21">
<path d="M292.3 47.8v25.4h-3.8M160.2 66.8h12.7M354.5 79.5h-17.8v-31.7h-85v43.1h-10.2M79 255.9h20.3"/>
<circle cx="307.5" cy="68.1" r=".51"/>
</g>
<circle cx="251.7" cy="74.4" r=".51" fill="#0dab76"/>
<circle cx="251.7" cy="74.4" r=".51" fill="none" stroke="#0dab76" stroke-width=".21"/>
<circle cx="292.3" cy="47.8" r=".51" fill="#0dab76"/>
<g fill="none" stroke="#0dab76" stroke-width=".21">
<path d="M219.9 77v8.9M241.5 74.4h10.2M219.9 84.6h6.4v6.3h7.6M249.1 163.3h10.2"/>
<circle cx="292.3" cy="47.8" r=".51"/>
</g>
<circle cx="219.9" cy="84.6" r=".51" fill="#0dab76"/>
<g fill="none" stroke="#0dab76" stroke-width=".21">
<path d="M219.9 77h6.4"/>
<circle cx="219.9" cy="84.6" r=".51"/>
</g>
<use href="#words"/>
</svg>
